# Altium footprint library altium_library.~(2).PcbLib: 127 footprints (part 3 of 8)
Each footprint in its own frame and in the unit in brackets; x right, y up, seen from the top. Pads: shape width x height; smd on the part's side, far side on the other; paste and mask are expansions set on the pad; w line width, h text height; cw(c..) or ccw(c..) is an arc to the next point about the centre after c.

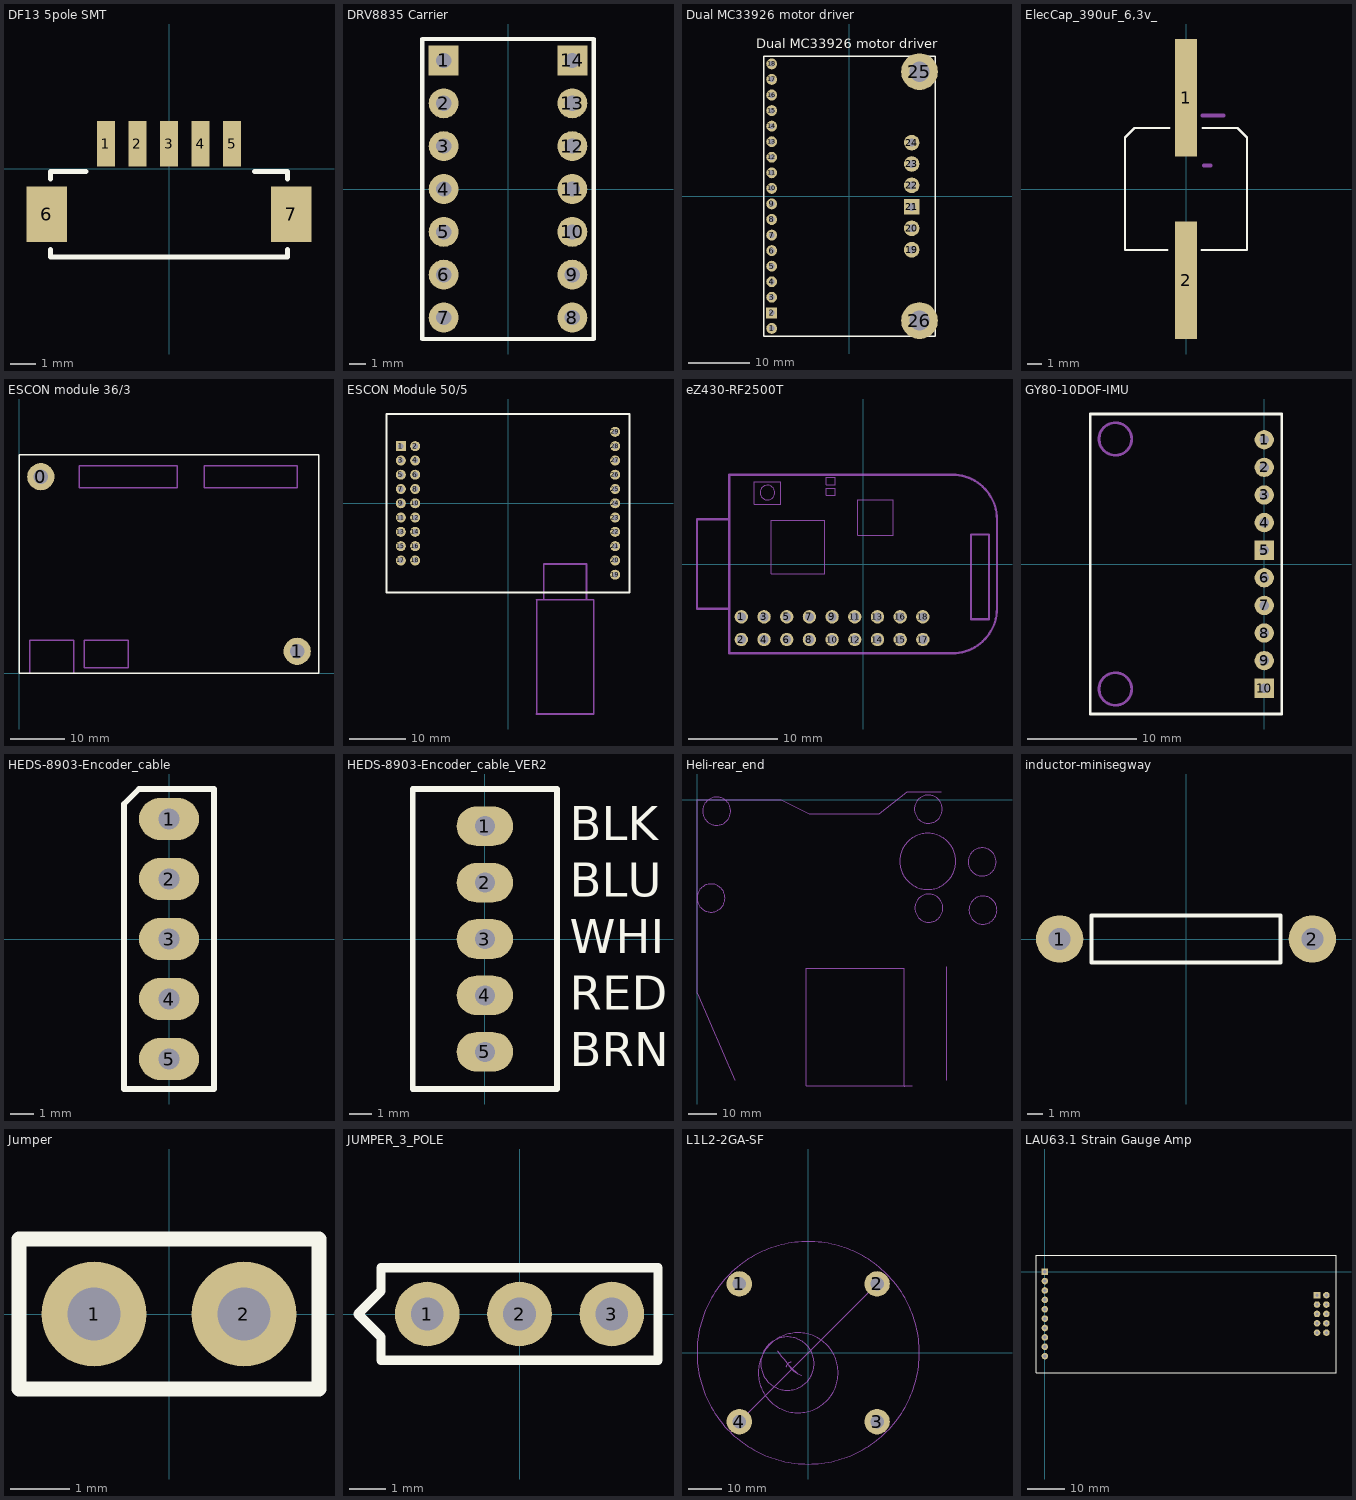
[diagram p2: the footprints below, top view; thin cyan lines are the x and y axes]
## DF13 5pole SMT [mm] "DF13-5P-1.25V(50) HIROSE (HRS)"
pads (7):
  rect 0.7x1.8 smd: 1(-2.5,1) 2(-1.25,1) 3(0,1) 4(1.25,1) 5(2.5,1)
  rect 1.6x2.2 smd: 6(-4.85,-1.8) 7(4.85,-1.8)
Top Overlay:
  lines w0.203: -4.7,-3.2 -4.7,-3.5 4.7,-3.5 4.7,-3.2 ; -4.7,-0.4 -4.7,-0.1 -3.3,-0.1 ; 3.4,-0.1 4.7,-0.1 4.7,-0.4

## DRV8835 Carrier [mil] "DRV8835 Dual Motor Driver Carrier Pololu"
pads (14):
  rect 70x70 hole 35.43: 1(-150,300) 14(150,300)
  round 70 hole 35.43: 2(-150,200) 3(-150,100) 4(-150,0) 5(-150,-100) 6(-150,-200) 7(-150,-300) 8(150,-300) 9(150,-200) 10(150,-100) 11(150,0) 12(150,100) 13(150,200)
Top Overlay:
  lines w10: -200,-350 -200,0 -200,350 200,350 200,-350 -200,-350

## Dual MC33926 motor driver [mil]
pads (26):
  round 70 hole 35.43: 1(-500,-850) 3(-500,-650) 4(-500,-550) 5(-500,-450) 6(-500,-350) 7(-500,-250) 8(-500,-150) 9(-500,-50) 10(-500,50) 11(-500,150) 12(-500,250) 13(-500,350) 14(-500,450) 15(-500,550) 16(-500,650) 17(-500,750) 18(-500,850)
  rect 70x70 hole 35.43: 2(-500,-750)
  round 100 hole 50: 19(400,-344.49) 20(400,-206.69) 22(400,68.9) 23(400,206.69) 24(400,344.49)
  rect 100x100 hole 50: 21(400,-68.9)
  round 236.22 hole 129.92: 25(450,800) 26(450,-800)
Top Overlay:
  lines w10: -550,-900 550,-900 550,900 -550,900 -550,-900
  text "Dual MC33926 motor driver" at -600,950 h60

## ElecCap_390uF_6,3v_ [mm]
height 6.9
pads (2):
  rect 1.5x8 smd: 1(0,6.2) 2(0,-6.2)
Top Overlay:
  lines w0.152: -1.25,-4.15 -4.15,-4.15 -4.15,3.5 -3.5,4.15 -1.125,4.15 ; 1.05,-4.15 4.15,-4.15 4.15,3.5 3.5,4.15 1.125,4.15
Mechanical 1:
  lines w0.254: 1.125,5 2.55,5 ; 1.225,1.6 1.675,1.6

## ESCON module 36/3 [mm]
pads (2):
  round 5 hole 2.7: 0(4,36) 1(51,4)
Top Overlay:
  lines w0.254: 0,0 55,0 55,40 0,40 0,0
Mechanical 1:
  lines w0.254: 2,0 2,6 10,6 10,0 ; 11,34 11,38 29,38 29,34 11,34 ; 12,1 12,2 12,6 20,6 20,1 12,1 ; 34,34 34,38 51,38 51,34 34,34

## ESCON Module 50/5 [mil]
pads (29):
  rect 70x70 hole 39.37: 1(-750,400)
  round 70 hole 39.37: 2(-650,400) 3(-750,300) 4(-650,300) 5(-750,200) 6(-650,200) 7(-750,100) 8(-650,100) 9(-750,0) 10(-650,0) 11(-750,-100) 12(-650,-100) 13(-750,-200) 14(-650,-200) 15(-750,-300) 16(-650,-300) 17(-750,-400) 18(-650,-400) 19(750,-500) 20(750,-400) 21(750,-300) 22(750,-200) 23(750,-100) 24(750,0) 25(750,100) 26(750,200) 27(750,300) 28(750,400) 29(750,500)
Top Overlay:
  lines w12: -850,-625 -850,625 850,625 850,-625 -850,-625
Mechanical 1:
  lines w10: 200,-1475 200,-675 ; 600,-1475 600,-675
  lines w12: 200,-1475 600,-1475 ; 200,-675 600,-675 ; 250,-675 250,-425 550,-425 550,-675 250,-675

## eZ430-RF2500T [mm] "eZ430-RF2500T TI wireless module"
pads (18):
  round 1.5 hole 1: 1(-13.63,-5.917) 2(-13.63,-8.457) 3(-11.09,-5.917) 4(-11.09,-8.457) 5(-8.55,-5.917) 6(-8.55,-8.457) 7(-6.01,-5.917) 8(-6.01,-8.457) 9(-3.47,-5.917) 10(-3.47,-8.457) 11(-0.93,-5.917) 12(-0.93,-8.457) 13(1.61,-5.917) 14(1.61,-8.457) 15(4.15,-8.457) 16(4.15,-5.917) 17(6.69,-8.457) 18(6.69,-5.917)
Mechanical 1:
  lines w0.254: -15,-5 -18.6,-5 -18.6,5 -15,5 ; -15,-10 10,-10 ccw(c10,-5) 15,-5 15,5 ccw(c10,5) 10,10 -15,10 -15,-10 ; 12.1,-6.2 12.1,3.3 14.1,3.3 14.1,-6.2 12.1,-6.2
Mechanical 6:
  circle w0.025: c-10.7,8 r0.825
  lines w0.025: -12.2,6.7 -9.2,6.7 -9.2,9.2 -12.2,9.2 -12.2,6.7 ; -10.3,-1.1 -4.3,-1.1 -4.3,4.9 -10.3,4.9 -10.3,-1.1 ; -4.1,7.7 -3.1,7.7 -3.1,8.5 -4.1,8.5 -4.1,7.7 ; -4.1,8.9 -3.1,8.9 -3.1,9.7 -4.1,9.7 -4.1,8.9 ; -0.6,3.2 -0.6,7.2 3.4,7.2 3.4,3.2 -0.6,3.2

## GY80-10DOF-IMU [mil]
pads (10):
  round 70 hole 35.43: 1(0,450) 2(0,350) 3(0,250) 4(0,150) 6(0,-50) 7(0,-150) 8(0,-250) 9(0,-350)
  rect 70x70 hole 35.43: 5(0,50) 10(0,-450)
Top Overlay:
  lines w10: -629.92,-543.31 62.99,-543.31 62.99,543.31 -629.92,543.31 -629.92,-543.31
Mechanical 1:
  circle w10: c-539.37,452.76 r59.06
  circle w10: c-539.37,-452.76 r59.06

## HEDS-8903-Encoder_cable [mil] "Encoder Cable for HEDS-5? Avago"
pads (5):
  oval 100x70 hole 35.43: 1(0,200) 2(0,100) 3(0,0) 4(0,-100) 5(0,-200)
Top Overlay:
  lines w10: -75,-250 75,-250 75,250 -50,250 -75,225 -75,-250

## HEDS-8903-Encoder_cable_VER2 [mil] "Encoder Cable for HEDS-5? Avago"
pads (5):
  oval 100x70 hole 35.43: 1(0,200) 2(0,100) 3(0,0) 4(0,-100) 5(0,-200)
Top Overlay:
  lines w10: -127.95,-265.75 127.95,-265.75 127.95,265.75 -127.95,265.75 -127.95,-265.75
  text "RED" at 150,-125 h60
  text "BRN" at 150,-225 h60
  text "WHI" at 150,-25 h60
  text "BLU" at 150,75 h60
  text "BLK" at 150,175 h60

## Heli-rear_end [mil]
Mechanical 3:
  circle w12: c4015.75,-1547.24 r196.85
  circle w12: c3255.91,-1519.69 r196.85
  circle w12: c4003.94,-870.08 r196.85
  circle w12: c3240.16,-862.2 r393.7
  circle w12: c3248.03,-129.92 r196.85
  circle w12: c196.85,-1377.95 r196.85
  circle w12: c275.59,-157.48 r196.85
  lines w10: 527.56,-3937.01 0,-2716.54 0,0 1181.1,0 1574.8,-196.85 2559.06,-196.85 2952.76,118.11 3429.13,118.11 ; 2917.32,-4023.62 2913.39,-4019.68 2913.39,-2362.2 1535.43,-2362.2 1535.43,-4015.75 3023.62,-4015.75 ; 3503.94,-3937.01 3503.94,-2342.52

## inductor-minisegway [mm]
pads (2):
  round 3 hole 1.4: 1(-8,0) 2(8,0)
Top Overlay:
  lines w0.254: -6,-1.5 -6,1.5 6,1.5 6,-1.5 -6,-1.5

## Jumper [mil]
pads (2):
  round 70 hole 35.43: 1(-50,0) 2(50,0)
Top Overlay:
  lines w10: -100,-50 100,-50 100,50 -100,50 -100,-50

## JUMPER_3_POLE [mil]
pads (3):
  round 70 hole 35.43: 1(-100,0) 2(0,0) 3(100,0)
Top Overlay:
  lines w10: -175,0 -150,25 -150,50 -100,50 150,50 150,-50 -150,-50 -150,-25 -175,0

## L1L2-2GA-SF [mil] "RTK GPS ANTENNA"
pads (4):
  round 300 hole 157.48: 1(-814.5,814.5) 2(814.5,814.5) 3(814.5,-814.5) 4(-814.5,-814.5)
Mechanical 1:
  circle w10: c-118.11,-236.22 r472.44
  circle w10: c0,0 r1314.96
  lines w10: -814.5,-814.5 814.5,814.5 ; -229.31,-152.87 ccw(c0,0) -75.71,-264.99
Mechanical 3:
  circle w10: c-246.06,-127.95 r314.96
  lines w10: -363.69,26.67 ccw(c814.5,814.5) -124.02,-247.57 ; -264.68,-174.06 cw(c-187.01,-187.01) -203.51,-110.02

## LAU63.1 Strain Gauge Amp [mil]
pads (20):
  rect 70x70 hole 35: 0(0,0) 10(2900,-250)
  round 70 hole 35: 1(0,-100) 2(0,-200) 3(0,-300) 4(0,-400) 5(0,-500) 6(0,-600) 7(0,-700) 8(0,-800) 9(0,-900) 11(3000,-250) 12(2900,-350) 13(3000,-350) 14(2900,-450) 15(3000,-450) 16(2900,-550) 17(3000,-550) 18(2900,-650) 19(3000,-650)
Top Overlay:
  lines w10: -94.49,-1078.74 -94.49,177.17 1345.28,177.17 3102.36,177.17 3102.36,-1078.74 -94.49,-1078.74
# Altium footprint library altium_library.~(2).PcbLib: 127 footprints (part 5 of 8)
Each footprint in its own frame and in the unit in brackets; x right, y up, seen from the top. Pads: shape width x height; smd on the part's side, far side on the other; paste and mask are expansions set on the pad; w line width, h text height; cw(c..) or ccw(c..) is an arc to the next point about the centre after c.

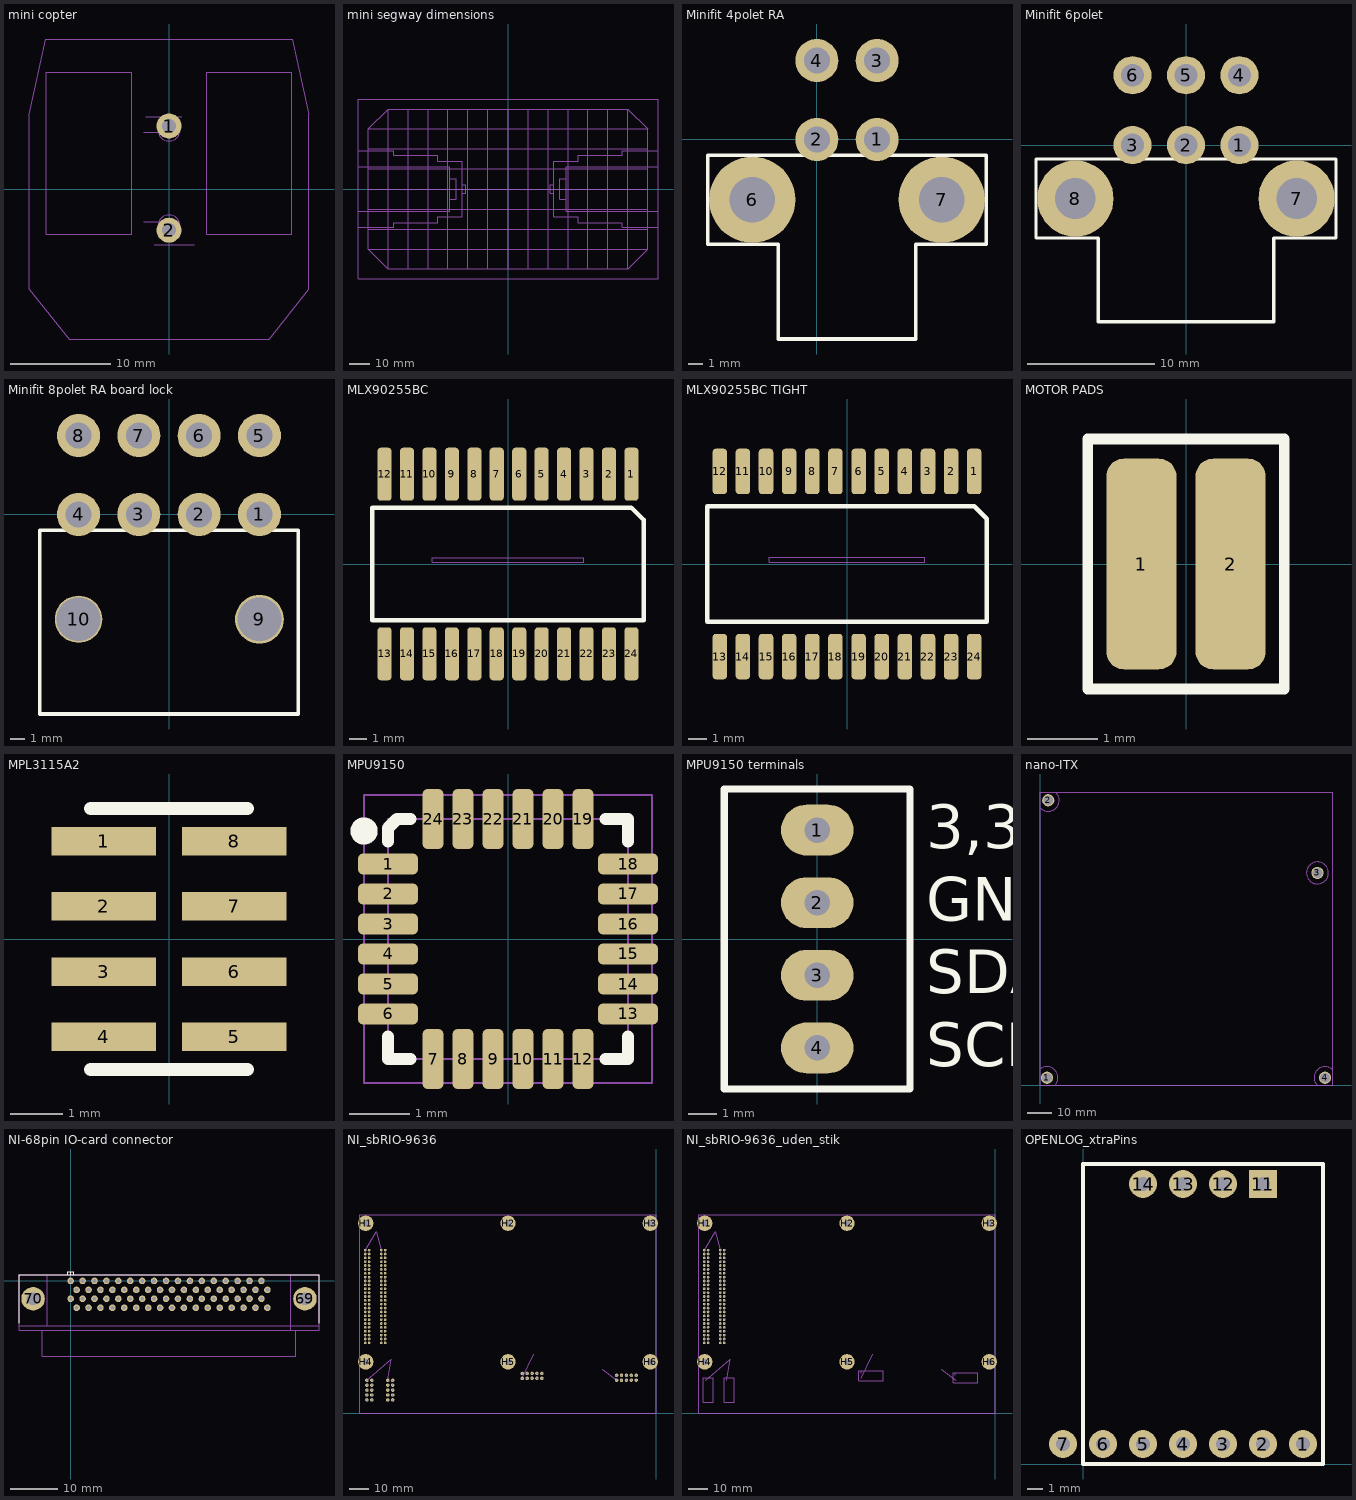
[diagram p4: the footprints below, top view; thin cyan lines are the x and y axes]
## mini copter [mm]
pads (2):
  round 2.5 hole 1.4 mask+0.05: 1(0,6.3) 2(0,-4.12)
Mechanical 3:
  circle w0.1: c0,5.9 r1.1
  circle w0.1: c0,-3.7 r1.1
  lines w0.05: -2.5,-3.3 1.1,-3.3 ; -2.5,5.7 1.1,5.7 ; -2.3,7.2 1.3,7.2 ; -1.5,-5.6 2.5,-5.6 ; -0.8,-3.7 0.5,-3.7 ; -0.4,5.9 1,5.9 ; 0,-4.4 0,-3.1 ; 0,5.1 0,6.5
  lines w0.1: -12.25,-4.5 -12.25,11.7 -3.75,11.7 -3.75,-4.5 -12.25,-4.5 ; 3.75,-4.5 3.75,11.7 12.25,11.7 12.25,-4.5 3.75,-4.5
Mechanical 5:
  lines w0.1: -14,-10 -10,-15 10,-15 14,-10 14,7.5 12.3,15 -12.3,15 -14,7.5 -14,-10

## mini segway dimensions [mil]
Mechanical 3:
  lines w10: -2952.76,-748.03 -2244.09,-748.03 -2244.09,-669.29 -1377.95,-669.29 -1377.95,-551.18 -905.51,-551.18 -905.51,551.18 -1377.95,551.18 -1377.95,669.29 -2244.09,669.29 -2244.09,748.03 -2952.76,748.03 ; -2952.76,-433.07 -1141.73,-433.07 -1141.73,196.85 ; -2952.76,433.07 -1141.73,433.07 -1141.73,196.85 ; -1141.73,-196.85 -1023.62,-196.85 -1023.62,196.85 -1141.73,196.85 ; -905.51,-78.74 -826.77,-78.74 -826.77,78.74 -905.51,78.74 ; 905.51,-78.74 826.77,-78.74 826.77,78.74 905.51,78.74 ; 1141.73,196.85 1023.62,196.85 1023.62,-196.85 1141.73,-196.85 ; 2952.76,-748.03 2244.09,-748.03 2244.09,-669.29 1377.95,-669.29 1377.95,-551.18 905.51,-551.18 905.51,551.18 1377.95,551.18 1377.95,669.29 2244.09,669.29 2244.09,748.03 2952.76,748.03 ; 2952.76,-433.07 1141.73,-433.07 1141.73,-196.85 ; 2952.76,433.07 1141.73,433.07 1141.73,-196.85 ; -2952.76,-1771.65 2952.76,-1771.65 2952.76,1771.65 -2952.76,1771.65 -2952.76,-1771.65
Mechanical 6:
  lines w10: -2755.91,-787.4 2755.91,-787.4 ; -2755.91,-393.7 2755.91,-393.7 ; -2755.91,0 2755.91,0 ; -2755.91,393.7 2755.91,393.7 ; -393.7,-1574.8 -393.7,1574.8 -787.4,1574.8 -787.4,-1574.8 -1181.1,-1574.8 -1181.1,1574.8 -1574.8,1574.8 -1574.8,-1574.8 -1968.5,-1574.8 -1968.5,1574.8 -2362.2,1574.8 ; 0,1574.8 0,-1574.8 ; 393.7,-1574.8 393.7,1574.8 ; 492.13,1574.8 984.25,1574.8 ; 787.4,-1574.8 787.4,1574.8 ; 1181.1,-1574.8 1181.1,1574.8 ; 1574.8,-1574.8 1574.8,1574.8 ; 1968.5,-1574.8 1968.5,1574.8 ; 2755.91,787.4 -2755.91,787.4 -2755.91,1181.1 ; -2755.91,-1181.1 -2755.91,1181.1 ; -2755.91,-1181.1 -2362.2,-1574.8 ; -2755.91,-1181.1 2755.91,-1181.1 ; -2755.91,1181.1 -2362.2,1574.8 ; -2755.91,1181.1 -2755.91,1181.1 ; -2755.91,1181.1 2755.91,1181.1 ; -2362.2,-1574.8 -2263.78,-1574.8 0,-1574.8 ; -2362.2,-1574.8 -2362.2,1574.8 ; -2362.2,1574.8 2362.2,1574.8 ; 0,-1574.8 2362.2,-1574.8 ; 2362.2,-1574.8 2755.91,-1181.1 ; 2362.2,-1574.8 2362.2,-1574.8 ; 2362.2,-1574.8 2362.2,1574.8 ; 2362.2,1574.8 2755.91,1181.1 ; 2755.91,-1181.1 2755.91,1181.1 ; 2755.91,1181.1 2755.91,1181.1

## Minifit 4polet RA [mm]
pads (6):
  round 3 hole 1.8: 1(4.2,0) 2(0,0) 3(4.2,5.5) 4(0,5.5)
  round 6 hole 3.2: 6(-4.5,-4.2) 7(8.7,-4.2)
Top Overlay:
  lines w0.254: -7.6,-7.3 -7.6,-1.1 11.8,-1.1 11.8,-7.3 6.9,-7.3 6.9,-13.9 -2.7,-13.9 -2.7,-7.3 -7.6,-7.3

## Minifit 6polet [mm]
pads (8):
  round 3 hole 1.8: 1(4.2,0) 2(0,0) 3(-4.2,0) 4(4.2,5.5) 5(0,5.5) 6(-4.2,5.5)
  round 6 hole 3.2: 7(8.7,-4.2) 8(-8.7,-4.2)
Top Overlay:
  lines w0.254: -11.8,-7.3 -6.9,-7.3 -6.9,-13.9 6.9,-13.9 6.9,-7.3 11.8,-7.3 11.8,-1.1 -11.8,-1.1 -11.8,-7.3

## Minifit 8polet RA board lock [mm]
pads (10):
  round 3 hole 1.8: 1(6.3,0) 2(2.1,0) 3(-2.1,0) 4(-6.3,0) 5(6.3,5.5) 6(2.1,5.5) 7(-2.1,5.5) 8(-6.3,5.5)
  round 3.4 hole 3.05: 9(6.3,-7.3)
  round 3.3 hole 3.05: 10(-6.3,-7.3)
Top Overlay:
  lines w0.254: -9,-13.9 9,-13.9 9,-7.3 9,-1.1 -9,-1.1 -9,-7.3 -9,-13.9

## MLX90255BC [mm] "Ptohodiode Array 128"
pads (24):
  rrect50% 0.8x3 smd: 1(6.985,5.08) 2(5.715,5.08) 3(4.445,5.08) 4(3.175,5.08) 5(1.905,5.08) 6(0.635,5.08) 7(-0.635,5.08) 8(-1.905,5.08) 9(-3.175,5.08) 10(-4.445,5.08) 11(-5.715,5.08) 12(-6.985,5.08) 13(-6.985,-5.08) 14(-5.715,-5.08) 15(-4.445,-5.08) 16(-3.175,-5.08) 17(-1.905,-5.08) 18(-0.635,-5.08) 19(0.635,-5.08) 20(1.905,-5.08) 21(3.175,-5.08) 22(4.445,-5.08) 23(5.715,-5.08) 24(6.985,-5.08)
Top Overlay:
  lines w0.254: -7.67,-3.175 7.67,-3.175 7.67,2.49 6.985,3.175 -7.67,3.175 -7.67,-3.175
  text "." at 7.62,3.175 h1.27
Mechanical 1:
  lines w0.025: -4.282,0.103 -4.282,0.363 4.282,0.363 4.282,0.103 -4.282,0.103

## MLX90255BC TIGHT [mm] "Ptohodiode Array 128"
pads (24):
  rrect50% 0.8x2.5 smd: 1(6.985,5.08) 2(5.715,5.08) 3(4.445,5.08) 4(3.175,5.08) 5(1.905,5.08) 6(0.635,5.08) 7(-0.635,5.08) 8(-1.905,5.08) 9(-3.175,5.08) 10(-4.445,5.08) 11(-5.715,5.08) 12(-6.985,5.08) 13(-6.985,-5.08) 14(-5.715,-5.08) 15(-4.445,-5.08) 16(-3.175,-5.08) 17(-1.905,-5.08) 18(-0.635,-5.08) 19(0.635,-5.08) 20(1.905,-5.08) 21(3.175,-5.08) 22(4.445,-5.08) 23(5.715,-5.08) 24(6.985,-5.08)
Top Overlay:
  lines w0.254: -7.67,-3.175 7.67,-3.175 7.67,2.49 6.985,3.175 -7.67,3.175 -7.67,-3.175
  text "." at 7.62,3.175 h1.27
Mechanical 1:
  lines w0.025: -4.282,0.103 -4.282,0.363 4.282,0.363 4.282,0.103 -4.282,0.103

## MOTOR PADS [mm]
pads (2):
  rrect50% 1x3 smd mask+0.05: 1(-0.635,0) 2(0.635,0)
Top Overlay:
  lines w0.152: -1.397,-1.778 1.397,-1.778 1.397,1.778 -1.397,1.778 -1.397,-1.778
  text "." at -1.397,1.397 h1.52

## MPL3115A2 [mm] "MPL3115A2  I2C Precision Altimeter"
height 1
pads (8):
  rect 2x0.55 smd: 1(-1.25,1.875) 2(-1.25,0.625) 3(-1.25,-0.625) 4(-1.25,-1.875) 5(1.25,-1.875) 6(1.25,-0.625) 7(1.25,0.625) 8(1.25,1.875)
Top Layer:
  text "." at -2,3 h1.27
Top Overlay:
  lines w0.254: -1.5,-2.5 1.5,-2.5 ; -1.5,2.5 1.5,2.5
  text "." at -1,3 h1.27

## MPU9150 [mm]
height 2
pads (24):
  rrect50% 1x0.35 smd mask+0.075: 1(-2,1.25) 2(-2,0.75) 3(-2,0.25) 4(-2,-0.25) 5(-2,-0.75) 6(-2,-1.25) 13(2,-1.25) 14(2,-0.75) 15(2,-0.25) 16(2,0.25) 17(2,0.75) 18(2,1.25)
  rrect50% 0.35x1 smd mask+0.075: 7(-1.25,-2) 8(-0.75,-2) 9(-0.25,-2) 10(0.25,-2) 11(0.75,-2) 12(1.25,-2) 19(1.25,2) 20(0.75,2) 21(0.25,2) 22(-0.25,2) 23(-0.75,2) 24(-1.25,2)
Top Overlay:
  circle w0.254: c-2.4,1.8 r0.1
  lines w0.203: -2,-1.625 -2,-2 -1.625,-2 ; -2,1.625 -2,1.85 -1.85,2 -1.625,2 ; 1.625,-2 2,-2 2,-1.625 ; 1.625,2 2,2 2,1.625
Mechanical 1:
  lines w0.025: -2.4,-2.4 -2.4,2.4 2.4,2.4 2.4,-2.4 -2.4,-2.4 ; -2,-2 -2,2 2,2 2,-2 -2,-2

## MPU9150 terminals [mil] "MP9150 terminals"
pads (4):
  oval 100x70 hole 35.43: 1(0,150) 2(0,50) 3(0,-50) 4(0,-150)
Top Overlay:
  lines w10: -127.95,-206.69 -127.95,206.69 127.95,206.69 127.95,-206.69 -127.95,-206.69
  text "3,3V" at 150,125 h60
  text "GND" at 150,25 h60
  text "SDA" at 150,-75 h60
  text "SCL" at 150,-175 h60

## nano-ITX [mm] "form factor + holes nano itx"
pads (4):
  round 5 hole 4: 1(2.75,3) 2(3.26,116.76) 3(113.65,86.98) 4(116.76,3)
Mechanical 1:
  circle w0.508: c113.65,86.98 r4.5
  lines w0.254: 0,0 0,120 120,120 120,0 0,0
  lines w0.508: 0.18,113.479 ccw(c3.26,116.76) 6.58,119.798 ; 0.191,6.701 cw(c2.75,3) 6.294,0.227 ; 113.28,0.147 cw(c116.76,3) 119.753,6.36

## NI-68pin IO-card connector [mm]
pads (70):
  round 1.4 hole 0.8: 1(0,0) 2(1.27,-1.905) 3(2.54,0) 4(3.81,-1.905) 5(5.08,0) 6(6.35,-1.905) 7(7.62,0) 8(8.89,-1.905) 9(10.16,0) 10(11.43,-1.905) 11(12.7,0) 12(13.97,-1.905) 13(15.24,0) 14(16.51,-1.905) 15(17.78,0) 16(19.05,-1.905) 17(20.32,0) 18(21.59,-1.905) 19(22.86,0) 20(24.13,-1.905) 21(25.4,0) 22(26.67,-1.905) 23(27.94,0) 24(29.21,-1.905) 25(30.48,0) 26(31.75,-1.905) 27(33.02,0) 28(34.29,-1.905) 29(35.56,0) 30(36.83,-1.905) 31(38.1,0) 32(39.37,-1.905) 33(40.64,0) 34(41.91,-1.905) 35(0,-3.81) 36(1.27,-5.715) 37(2.54,-3.81) 38(3.81,-5.715) 39(5.08,-3.81) 40(6.35,-5.715) 41(7.62,-3.81) 42(8.89,-5.715) 43(10.16,-3.81) 44(11.43,-5.715) 45(12.7,-3.81) 46(13.97,-5.715) 47(15.24,-3.81) 48(16.51,-5.715) 49(17.78,-3.81) 50(19.05,-5.715) 51(20.32,-3.81) 52(21.59,-5.715) 53(22.86,-3.81) 54(24.13,-5.715) 55(25.4,-3.81) 56(26.67,-5.715) 57(27.94,-3.81) 58(29.21,-5.715) 59(30.48,-3.81) 60(31.75,-5.715) 61(33.02,-3.81) 62(34.29,-5.715) 63(35.56,-3.81) 64(36.83,-5.715) 65(38.1,-3.81) 66(39.37,-5.715) 67(40.64,-3.81) 68(41.91,-5.715)
  round 5 hole 2.7: 69(49.9,-3.81) 70(-8,-3.81)
Top Overlay:
  lines w0.254: -11,-9.017 -11,1.295 52.9,1.295 52.9,-9.017 ; -0.635,1.295 -0.635,1.905 0,1.905 ; 0,1.295 0,1.905 ; 0.635,1.295 0.635,1.905 0,1.905
Mechanical 1:
  lines w0.025: -5.994,-10.516 -6,-10.521 -6,-16 47.9,-16 47.9,-10.519 47.904,-10.515 ; -5,-9.515 -5,1.3 ; 46.9,-10.515 46.9,1.3 ; 52.9,-9.515 -11,-9.515 ; -11,-9.515 -11,1.3 52.9,1.3 52.9,-10.515 -11,-10.515 -11,-9.515

## NI_sbRIO-9636 [mm]
pads (146):
  round 8 hole 3.2: H1(-150.47,98.4) H2(-76.835,98.4) H3(-3.2,98.4) H4(-150.47,26.67) H5(-76.835,26.67) H6(-3.2,26.67)
  round 1.4 hole 0.8: J502-1(-150.724,84.506) J502-2(-148.724,84.506) J502-3(-150.724,82.506) J502-4(-148.724,82.506) J502-5(-150.724,80.506) J502-6(-148.724,80.506) J502-7(-150.724,78.506) J502-8(-148.724,78.506) J502-9(-150.724,76.506) J502-10(-148.724,76.506) J502-11(-150.724,74.506) J502-12(-148.724,74.506) J502-13(-150.724,72.506) J502-14(-148.724,72.506) J502-15(-150.724,70.506) J502-16(-148.724,70.506) J502-17(-150.724,68.506) J502-18(-148.724,68.506) J502-19(-150.724,66.506) J502-20(-148.724,66.506) J502-21(-150.724,64.506) J502-22(-148.724,64.506) J502-23(-150.724,62.506) J502-24(-148.724,62.506) J502-25(-150.724,60.506) J502-26(-148.724,60.506) J502-27(-150.724,58.506) J502-28(-148.724,58.506) J502-29(-150.724,56.506) J502-30(-148.724,56.506) J502-31(-150.724,54.506) J502-32(-148.724,54.506) J502-33(-150.724,52.506) J502-34(-148.724,52.506) J502-35(-150.724,50.506) J502-36(-148.724,50.506) J502-37(-150.724,48.506) J502-38(-148.724,48.506) J502-39(-150.724,46.506) J502-40(-148.724,46.506) J502-41(-150.724,44.506) J502-42(-148.724,44.506) J502-43(-150.724,42.506) J502-44(-148.724,42.506) J502-45(-150.724,40.506) J502-46(-148.724,40.506) J502-47(-150.724,38.506) J502-48(-148.724,38.506) J502-49(-150.724,36.506) J502-50(-148.724,36.506) J503-1(-142.418,84.506) J503-2(-140.418,84.506) J503-3(-142.418,82.506) J503-4(-140.418,82.506) J503-5(-142.418,80.506) J503-6(-140.418,80.506) J503-7(-142.418,78.506) J503-8(-140.418,78.506) J503-9(-142.418,76.506) J503-10(-140.418,76.506) J503-11(-142.418,74.506) J503-12(-140.418,74.506) J503-13(-142.418,72.506) J503-14(-140.418,72.506) J503-15(-142.418,70.506) J503-16(-140.418,70.506) J503-17(-142.418,68.506) J503-18(-140.418,68.506) J503-19(-142.418,66.506) J503-20(-140.418,66.506) J503-21(-142.418,64.506) J503-22(-140.418,64.506) J503-23(-142.418,62.506) J503-24(-140.418,62.506) J503-25(-142.418,60.506) J503-26(-140.418,60.506) J503-27(-142.418,58.506) J503-28(-140.418,58.506) J503-29(-142.418,56.506) J503-30(-140.418,56.506) J503-31(-142.418,54.506) J503-32(-140.418,54.506) J503-33(-142.418,52.506) J503-34(-140.418,52.506) J503-35(-142.418,50.506) J503-36(-140.418,50.506) J503-37(-142.418,48.506) J503-38(-140.418,48.506) J503-39(-142.418,46.506) J503-40(-140.418,46.506) J503-41(-142.418,44.506) J503-42(-140.418,44.506) J503-43(-142.418,42.506) J503-44(-140.418,42.506) J503-45(-142.418,40.506) J503-46(-140.418,40.506) J503-47(-142.418,38.506) J503-48(-140.418,38.506) J503-49(-142.418,36.506) J503-50(-140.418,36.506)
  round 1.778 hole 1: W500-1(-69.469,18.136) W500-2(-69.469,20.676) W500-3(-66.929,18.136) W500-4(-66.929,20.676) W500-5(-64.389,18.136) W500-6(-64.389,20.676) W500-7(-61.849,18.136) W500-8(-61.849,20.676) W500-9(-59.309,18.136) W500-10(-59.309,20.676) W501-1(-20.625,17.17) W501-2(-20.625,19.71) W501-3(-18.085,17.17) W501-4(-18.085,19.71) W501-5(-15.545,17.17) W501-6(-15.545,19.71) W501-7(-13.005,17.17) W501-8(-13.005,19.71) W501-9(-10.465,17.17) W501-10(-10.465,19.71) W502-1(-149.86,17.12) W502-2(-147.32,17.12) W502-3(-149.86,14.58) W502-4(-147.32,14.58) W502-5(-149.86,12.04) W502-6(-147.32,12.04) W502-7(-149.86,9.5) W502-8(-147.32,9.5) W502-9(-149.86,6.96) W502-10(-147.32,6.96) W503-1(-139.065,17.12) W503-2(-136.525,17.12) W503-3(-139.065,14.58) W503-4(-136.525,14.58) W503-5(-139.065,12.04) W503-6(-136.525,12.04) W503-7(-139.065,9.5) W503-8(-136.525,9.5) W503-9(-139.065,6.96) W503-10(-136.525,6.96)
Mechanical 3:
  lines w0.254: -150.724,84.506 -145,94 -142.418,84.506 ; -149.86,17.12 -137.16,27.94 -139.065,17.12 ; -69.469,18.136 -63.5,30.48 ; -27.94,22.86 -20.625,17.17
Mechanical 5:
  lines w0.254: -153.67,0 0,0 0,102.87 -153.67,102.87 -153.67,0

## NI_sbRIO-9636_uden_stik [mm]
pads (106):
  round 8 hole 3.2: H1(-150.47,98.4) H2(-76.835,98.4) H3(-3.2,98.4) H4(-150.47,26.67) H5(-76.835,26.67) H6(-3.2,26.67)
  round 1.4 hole 0.8: J502-1(-150.724,84.506) J502-2(-148.724,84.506) J502-3(-150.724,82.506) J502-4(-148.724,82.506) J502-5(-150.724,80.506) J502-6(-148.724,80.506) J502-7(-150.724,78.506) J502-8(-148.724,78.506) J502-9(-150.724,76.506) J502-10(-148.724,76.506) J502-11(-150.724,74.506) J502-12(-148.724,74.506) J502-13(-150.724,72.506) J502-14(-148.724,72.506) J502-15(-150.724,70.506) J502-16(-148.724,70.506) J502-17(-150.724,68.506) J502-18(-148.724,68.506) J502-19(-150.724,66.506) J502-20(-148.724,66.506) J502-21(-150.724,64.506) J502-22(-148.724,64.506) J502-23(-150.724,62.506) J502-24(-148.724,62.506) J502-25(-150.724,60.506) J502-26(-148.724,60.506) J502-27(-150.724,58.506) J502-28(-148.724,58.506) J502-29(-150.724,56.506) J502-30(-148.724,56.506) J502-31(-150.724,54.506) J502-32(-148.724,54.506) J502-33(-150.724,52.506) J502-34(-148.724,52.506) J502-35(-150.724,50.506) J502-36(-148.724,50.506) J502-37(-150.724,48.506) J502-38(-148.724,48.506) J502-39(-150.724,46.506) J502-40(-148.724,46.506) J502-41(-150.724,44.506) J502-42(-148.724,44.506) J502-43(-150.724,42.506) J502-44(-148.724,42.506) J502-45(-150.724,40.506) J502-46(-148.724,40.506) J502-47(-150.724,38.506) J502-48(-148.724,38.506) J502-49(-150.724,36.506) J502-50(-148.724,36.506) J503-1(-142.418,84.506) J503-2(-140.418,84.506) J503-3(-142.418,82.506) J503-4(-140.418,82.506) J503-5(-142.418,80.506) J503-6(-140.418,80.506) J503-7(-142.418,78.506) J503-8(-140.418,78.506) J503-9(-142.418,76.506) J503-10(-140.418,76.506) J503-11(-142.418,74.506) J503-12(-140.418,74.506) J503-13(-142.418,72.506) J503-14(-140.418,72.506) J503-15(-142.418,70.506) J503-16(-140.418,70.506) J503-17(-142.418,68.506) J503-18(-140.418,68.506) J503-19(-142.418,66.506) J503-20(-140.418,66.506) J503-21(-142.418,64.506) J503-22(-140.418,64.506) J503-23(-142.418,62.506) J503-24(-140.418,62.506) J503-25(-142.418,60.506) J503-26(-140.418,60.506) J503-27(-142.418,58.506) J503-28(-140.418,58.506) J503-29(-142.418,56.506) J503-30(-140.418,56.506) J503-31(-142.418,54.506) J503-32(-140.418,54.506) J503-33(-142.418,52.506) J503-34(-140.418,52.506) J503-35(-142.418,50.506) J503-36(-140.418,50.506) J503-37(-142.418,48.506) J503-38(-140.418,48.506) J503-39(-142.418,46.506) J503-40(-140.418,46.506) J503-41(-142.418,44.506) J503-42(-140.418,44.506) J503-43(-142.418,42.506) J503-44(-140.418,42.506) J503-45(-142.418,40.506) J503-46(-140.418,40.506) J503-47(-142.418,38.506) J503-48(-140.418,38.506) J503-49(-142.418,36.506) J503-50(-140.418,36.506)
Mechanical 3:
  lines w0.254: -150.724,84.506 -145,94 -142.418,84.506 ; -149.86,17.12 -137.16,27.94 -139.065,17.12 ; -69.469,18.136 -63.5,30.48 ; -69.469,20.676 -69.469,21.946 ; -27.94,22.86 -20.625,17.17 ; -20.701,19.66 -20.701,20.93 ; -151.13,5.715 -151.13,18.415 -146.05,18.415 -146.05,5.715 -151.13,5.715 ; -140.335,5.715 -140.335,18.415 -135.255,18.415 -135.255,5.715 -140.335,5.715 ; -70.739,16.866 -70.739,21.946 -58.039,21.946 -58.039,16.866 -70.739,16.866 ; -21.971,15.85 -9.271,15.85 -9.271,20.93 -21.971,20.93 -21.971,15.85
Mechanical 5:
  lines w0.254: -153.67,0 0,0 0,102.87 -153.67,102.87 -153.67,0

## OPENLOG_xtraPins [mil] "Openlag with AVR facing down, inc xtra pins"
pads (11):
  round 70 hole 35.43: 1(550,50) 2(450,50) 3(350,50) 4(250,50) 5(150,50) 6(50,50) 7(-50,50) 12(350,700) 13(250,700) 14(150,700)
  rect 70x70 hole 35.43: 11(450,700)
Top Overlay:
  lines w10: 0,0 0,750 600,750 600,0 0,0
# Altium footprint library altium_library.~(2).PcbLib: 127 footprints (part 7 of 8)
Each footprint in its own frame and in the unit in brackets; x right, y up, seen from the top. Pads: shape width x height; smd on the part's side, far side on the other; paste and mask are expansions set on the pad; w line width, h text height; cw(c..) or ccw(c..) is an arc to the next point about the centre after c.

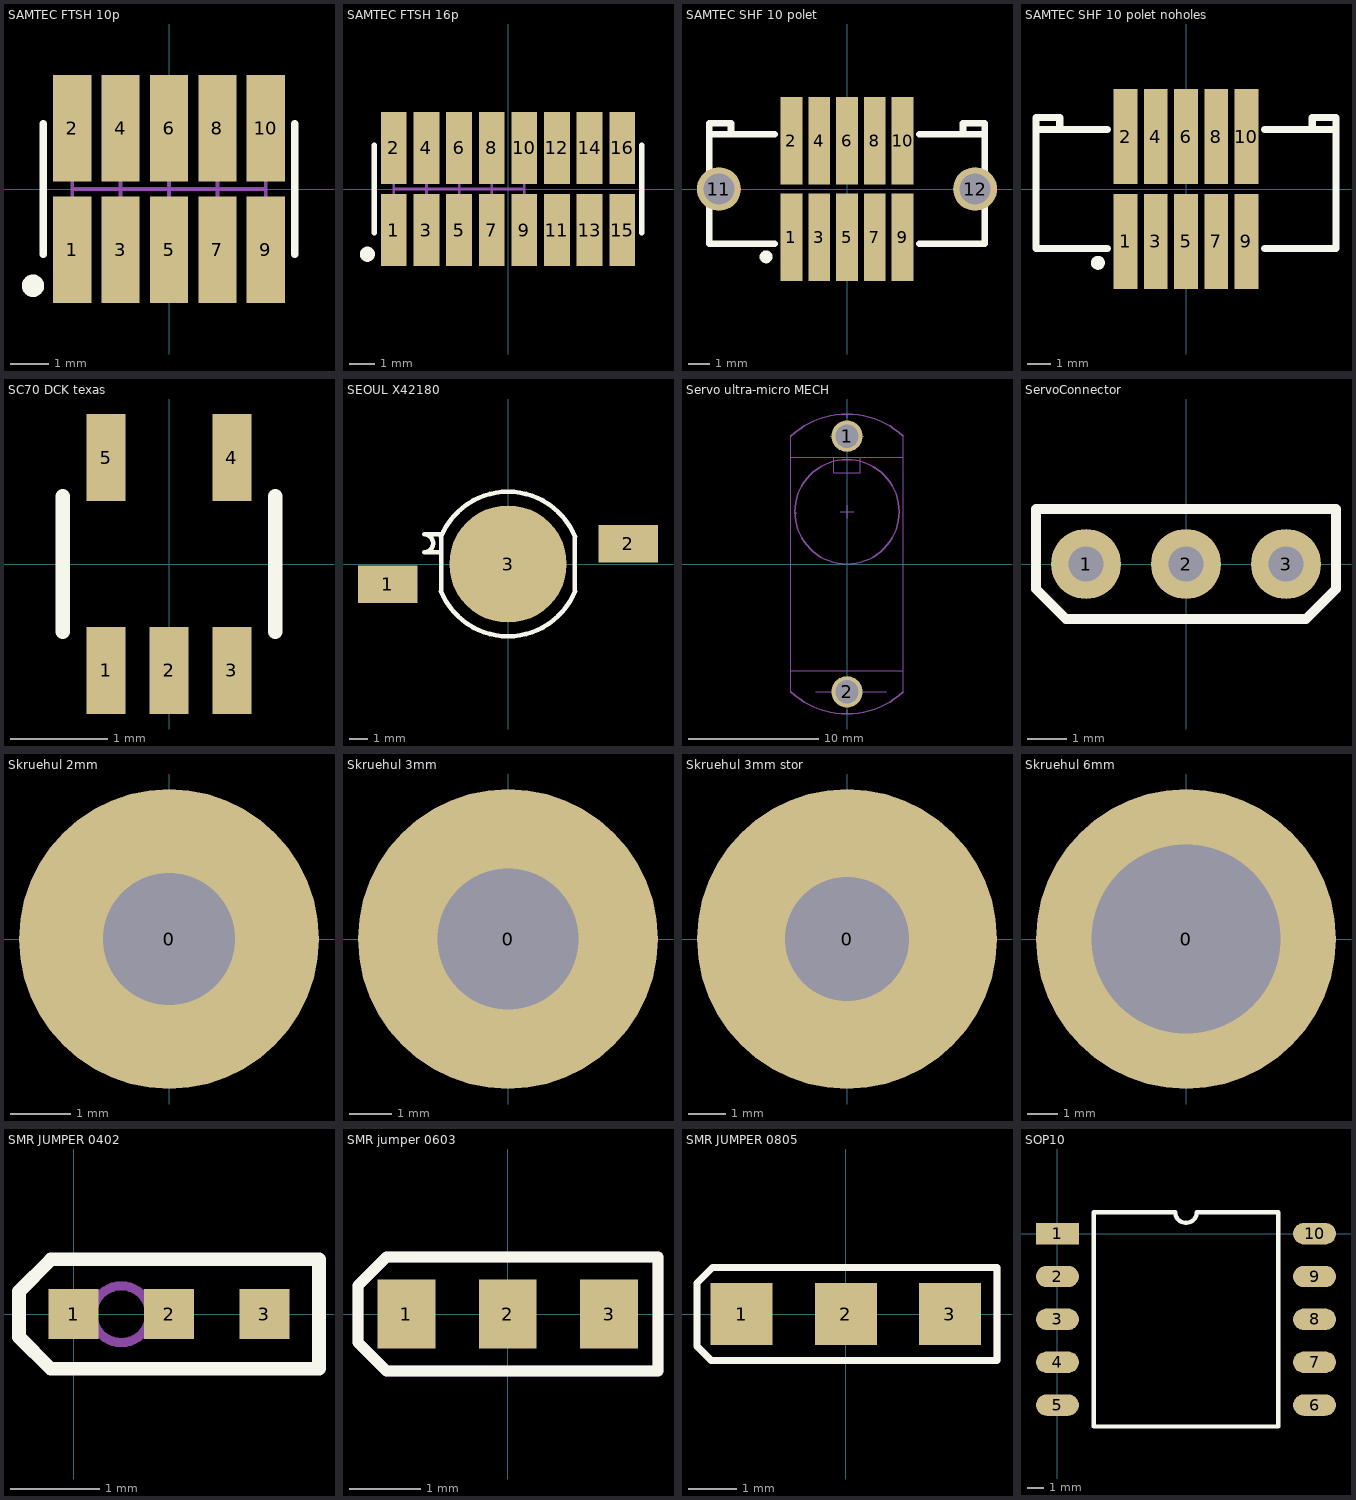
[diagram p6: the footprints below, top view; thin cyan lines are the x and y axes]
## SAMTEC FTSH 10p [mil] "samtec FTSH"
pads (10):
  rect 39.37x110 smd: 1(-100,-63) 2(-100,63) 3(-50,-63) 4(-50,63) 5(0,-63) 6(0,63) 7(50,-63) 8(50,63) 9(100,-63) 10(100,63)
Top Overlay:
  circle w12: c-140.57,-100 r5.57
  lines w8: -130,-67.5 -130,67.5 ; 130,-67.5 130,67.5
Mechanical 1:
  lines w3.94: -100,-25 -100,25 ; -100,0 100,0 ; -50,-25 -50,25 ; 0,-25 0,25 ; 50,-25 50,25 ; 100,-25 100,25
3D body: height 235.04, standoff 0, extent -124.99,-114.95 125,114.97

## SAMTEC FTSH 16p [mil] "samtec FTSH"
pads (16):
  rect 39.37x110 smd: 1(-175,-63) 2(-175,63) 3(-125,-63) 4(-125,63) 5(-75,-63) 6(-75,63) 7(-25,-63) 8(-25,63) 9(25,-63) 10(25,63) 11(75,-63) 12(75,63) 13(125,-63) 14(125,63) 15(175,-63) 16(175,63)
Top Overlay:
  circle w12: c-215.57,-100 r5.57
  lines w8: -205,-67.5 -205,67.5 ; 205,-67.5 205,67.5
Mechanical 1:
  lines w3.94: -175,-25 -175,25 ; -175,0 25,0 ; -125,-25 -125,25 ; -75,-25 -75,25 ; -25,-25 -25,25 ; 25,-25 25,25
3D body: height 235.04, standoff 0, extent -199.99,-114.95 50.01,114.97

## SAMTEC SHF 10 polet [mm] "suitable for JTAGICE3 connection"
pads (12):
  rect 1x4 smd: 1(-2.54,-2.2) 2(-2.54,2.2) 3(-1.27,-2.2) 4(-1.27,2.2) 5(0,-2.2) 6(0,2.2) 7(1.27,-2.2) 8(1.27,2.2) 9(2.54,-2.2) 10(2.54,2.2)
  round 2 hole 1.42: 11(-5.854,0) 12(5.854,0)
Top Overlay:
  circle w0.305: c-3.7,-3.1 r0.141
  lines w0.305: -5.3,2.5 -5.3,3 -6.3,3 -6.3,2.5 ; -3.3,-2.5 -6.3,-2.5 -6.3,2.5 ; -3.3,2.5 -6.3,2.5 ; 3.3,-2.5 6.3,-2.5 6.3,2.5 ; 3.3,2.5 6.3,2.5 ; 5.3,2.5 5.3,3 6.3,3 6.3,2.5

## SAMTEC SHF 10 polet noholes [mm] "suitable for JTAGICE3 connection"
pads (10):
  rect 1x4 smd: 1(-2.54,-2.2) 2(-2.54,2.2) 3(-1.27,-2.2) 4(-1.27,2.2) 5(0,-2.2) 6(0,2.2) 7(1.27,-2.2) 8(1.27,2.2) 9(2.54,-2.2) 10(2.54,2.2)
Top Overlay:
  circle w0.305: c-3.7,-3.1 r0.141
  lines w0.305: -5.3,2.5 -5.3,3 -6.3,3 -6.3,2.5 ; -3.3,-2.5 -6.3,-2.5 -6.3,2.5 ; -3.3,2.5 -6.3,2.5 ; 3.3,-2.5 6.3,-2.5 6.3,2.5 ; 3.3,2.5 6.3,2.5 ; 5.3,2.5 5.3,3 6.3,3 6.3,2.5

## SC70 DCK texas [mm]
pads (5):
  rect 0.4x0.9 smd mask+0.05: 1(-0.65,-1.1) 2(0,-1.1) 3(0.65,-1.1) 4(0.65,1.1) 5(-0.65,1.1)
Top Overlay:
  lines w0.15: -1.1,-0.7 -1.1,0.7 ; 1.1,-0.7 1.1,0.7

## SEOUL X42180 [mm]
pads (3):
  rect 3.3x2.1 smd: 1(-6.65,-1.12) 2(6.65,1.12)
  round 6.5 smd: 3(0,0)
Top Overlay:
  lines w0.254: -3.708,-1.503 ccw(c0,0) 3.708,-1.503 ; -3.708,1.503 cw(c0,0) 3.708,1.503 ; -3.7,-1.503 -3.7,1.643 -4.644,1.643 cw(c-4.644,1.143) -4.644,0.643 -3.7,0.643 ; 3.7,-1.503 3.7,1.503
3D body: height 5.08, standoff 0, extent -7.25,-4 7.25,3.966

## Servo ultra-micro MECH [mm] "HK-282A Servo ultra-micro  2g"
pads (2):
  round 2.4 hole 1.8 mask+0.05: 1(0,9.8) 2(0,-9.8)
Mechanical 3:
  circle w0.1: c0,9.8 r0.9
  circle w0.1: c0,-9.8 r0.9
  circle w0.1: c0,4 r4
  lines w0.05: -4.3,-9.8 -4.3,-8.2 ; -4.3,9.8 -4.3,8.2 ; -4,4 -3.9,3.9 ; -2.4,-9.8 3,-9.8 ; -1.3,9.8 1.3,9.8 ; -1,8.2 -1,7 1,7 1,8.2 ; -0.5,4 0.5,4 ; 0,-11.5 0,-11.2 ; 0,-10.3 0,-9.3 ; 0,3.5 0,4.5 ; 0,9.3 0,10.3 ; 0,11.2 0,11.5 ; 4.3,-9.8 4.3,-8.2 ; 4.3,9.8 4.3,8.2 ; -4.3,-8.2 4.3,-8.2 ; -4.3,-8.2 -4.3,8.2 ; -4.3,8.2 4.3,8.2 ; 4.3,-8.2 4.3,8.2
  lines w0.1: -4.3,-9.8 ccw(c0,-5.212) 4.3,-9.8 ; -4.3,9.8 cw(c0,5.212) 4.3,9.8
3D body: height 9.8, standoff -10.2, extent -4.2,-11.438 4.201,11.438

## ServoConnector [mil]
pads (3):
  round 70 hole 35.43: 1(-100,0) 2(0,0) 3(100,0)
Top Overlay:
  lines w10: -150,-25 -150,55 150,55 150,-25 120,-55 -120,-55 -150,-25

## Skruehul 2mm [mm] "2,2 mm copper ring 5mm"
pads (1):
  round 5 hole 2.2: 0(0,0)

## Skruehul 3mm [mm] "3,3 mm copper ring 7mm"
pads (1):
  round 7 hole 3.3: 0(0,0)

## Skruehul 3mm stor [mm] "3,3 mm copper ring 8mm"
pads (1):
  round 8 hole 3.3: 0(0,0)

## Skruehul 6mm [mm]
pads (1):
  round 10 hole 6.3: 0(0,0)

## SMR JUMPER 0402 [mil]
pads (3):
  rect 22x22 smd: 1(0,0) 2(42,0) 3(84,0)
Top Overlay:
  lines w6: -10,24 -24,10 -24,-10 -10,-24 108,-24 108,24 ; -10,24.2 108,24.2
Mechanical 3:
  lines w4: 8.5,0 cw(c21,0) 21,12.5 cw(c21,0) 33.5,0 cw(c21,0) 21,-12.5 cw(c21,0) 8.5,0
3D body: height 7.95, standoff 0, extent 1.32,-11.8 40.69,11.82

## SMR jumper 0603 [mil]
pads (3):
  rect 32x38 smd: 1(-56,0) 3(56,0)
  rect 32x38 smd mask+4: 2(0,0)
Top Overlay:
  lines w6: -82.68,-15.75 -82.68,15.75 -66.93,31.5 82.94,31.5 82.94,-31.5 -66.93,-31.5 -82.68,-15.75
Mechanical 1:
  lines w6: -82.68,-15.75 -82.68,15.75 -66.93,31.5 82.94,31.5 82.94,-31.5 -66.93,-31.5 -82.68,-15.75

## SMR JUMPER 0805 [mil]
pads (3):
  rect 50x50 smd: 1(-84.02,0) 2(0,0) 3(84,0)
Top Overlay:
  lines w6: -120,-26 -120,25 -107.5,37.5 122,37.5 122,-37.5 -108.5,-37.5 -120,-26
Mechanical 1:
  lines w6: 122,-37.5 122,37.5
3D body: height 30.79, standoff 0, extent -81.36,-24.6 -2.62,24.61

## SOP10 [mil]
pads (10):
  rect 100x50 smd: 1(0,0)
  oval 100x50 smd: 2(0,-100) 3(0,-200) 4(0,-300) 5(0,-400) 6(600,-400) 7(600,-300) 8(600,-200) 9(600,-100) 10(600,0)
Top Overlay:
  lines w10: 85,-450 515,-450 515,50 325,50 cw(c300,50) 275,50 85,50 85,-450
